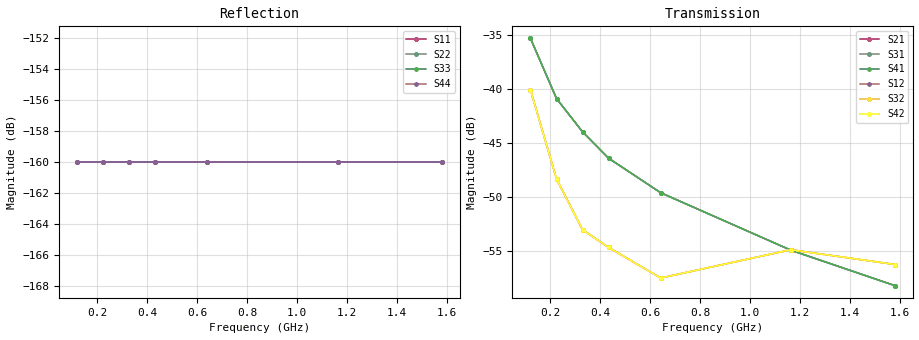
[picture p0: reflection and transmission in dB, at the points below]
! %Port labels%4
! %GPS
! %VHF
! %UHF
! %L_Band
# Hz S MA R 5.000000e+01
!  FREQ  |S11|  <S11  |S12|  <S12  |S13|  <S13  |S14|  <S14
!  |S21|  <S21  |S22|  <S22  |S23|  <S23  |S24|  <S24
!  |S31|  <S31  |S32|  <S32  |S33|  <S33  |S34|  <S34
!  |S41|  <S41  |S42|  <S42  |S43|  <S43  |S44|  <S44
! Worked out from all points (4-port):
!   15 points, 120 MHz to 1.58 GHz, reference 50 ohm
!   strongest paths, dB at 120 MHz, 432.9 MHz, 850 MHz, 1.267 GHz, 1.58 GHz:
!     S43: -42.2, -46.1, -49.0, -50.8, -51.9
!     S23: -42.2, -46.1, -49.0, -50.8, -51.9
!     S13: -42.2, -46.1, -49.0, -50.8, -51.9
!     S24: -35.1, -50.0, -47.8, -49.3, -51.2
!     S14: -35.1, -50.0, -47.8, -49.3, -51.2
!     S41: -35.3, -46.4, -52.0, -55.9, -58.2
!   lowest |S11| = - dB at 120 MHz (marker M1), VSWR 1.00, Z = 50 + j0 ohm
!   |S11| at or under -10 dB: start of sweep to end of sweep
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1.2e8  0 0.0  0.009941 139.1  0.007742 166.4  0.01759 148.0
       0.01721 16.2  0 0.0  0.007742 166.4  0.01759 148.0
       0.01721 16.2  0.009941 139.1  0 0.0  0.01759 148.0
       0.01721 16.2  0.009941 139.1  0.007742 166.4  0 0.0
2.242857e8  0 0.0  0.003842 110.9  0.006478 170.1  0.006939 -156.5
            0.009056 37.2  0 0.0  0.006478 170.1  0.006939 -156.5
            0.009056 37.2  0.003842 110.9  0 0.0  0.006939 -156.5
            0.009056 37.2  0.003842 110.9  0.006478 170.1  0 0.0
3.285714e8  0 0.0  0.002237 118.1  0.004326 141.5  0.006486 -121.2
            0.00635 57.2  0 0.0  0.004326 141.5  0.006486 -121.2
            0.00635 57.2  0.002237 118.1  0 0.0  0.006486 -121.2
            0.00635 57.2  0.002237 118.1  0.004326 141.5  0 0.0
4.328571e8  0 0.0  0.001851 106.1  0.004959 117.2  0.003148 -85.3
            0.004793 78.3  0 0.0  0.004959 117.2  0.003148 -85.3
            0.004793 78.3  0.001851 106.1  0 0.0  0.003148 -85.3
            0.004793 78.3  0.001851 106.1  0.004959 117.2  0 0.0
6.414286e8  0 0.0  0.001336 83.2  0.004366 67.2  0.003043 15.9
            0.003317 117.2  0 0.0  0.004366 67.2  0.003043 15.9
            0.003317 117.2  0.001336 83.2  0 0.0  0.003043 15.9
            0.003317 117.2  0.001336 83.2  0.004366 67.2  0 0.0
1.162857e9  0 0.0  0.001806 -26.4  0.003218 -59.0  0.004235 -161.0
            0.001797 -148.7  0 0.0  0.003218 -59.0  0.004235 -161.0
            0.001797 -148.7  0.001806 -26.4  0 0.0  0.004235 -161.0
            0.001797 -148.7  0.001806 -26.4  0.003218 -59.0  0 0.0
1.58e9  0 0.0  0.001543 -121.2  0.002552 -159.9  0.00277 -20.4
        0.001231 -73.5  0 0.0  0.002552 -159.9  0.00277 -20.4
        0.001231 -73.5  0.001543 -121.2  0 0.0  0.00277 -20.4
        0.001231 -73.5  0.001543 -121.2  0.002552 -159.9  0 0.0
